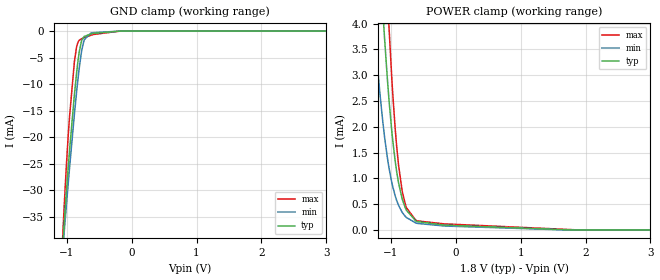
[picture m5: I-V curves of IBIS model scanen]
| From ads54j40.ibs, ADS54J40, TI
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|   scanen Model
[Model]   scanen
Model_type   Input
Vinl = 0.4
Vinh = 1.2
|   typ   min   max
|   (nom PVT)   (fast PVT)   (slow PVT)
|Average
C_comp   1.329e-12   1.282e-12   1.361e-12
| Where nom  PVT is Nominal Process, 1.8V, 25C
|   Fast PVT is Strong Process,  1.9V, -40C
|   Slow PVT is Weak Process,   1.7V, 85C
[Voltage Range]   1.8   1.7   1.9
|Ambient Temperature   25   85   -40
|Junction Temperature
[Temperature Range]   25   85   -40
[Power Clamp Reference]   1.8   1.7   1.9
[GND Clamp Reference]   0   0   0
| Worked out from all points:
|   GND clamp passes 1 mA (typ) near -0.73 V on its own axis
|   POWER clamp passes 1 mA (typ) near -0.90 V on its own axis
[GND Clamp]
|   Voltage   I(typ)   I(min)   I(max)
-1.8V     -253.9mA   -233.1mA   -272.1mA
-1.072V   -42.59mA   -42.97mA   -41.16mA
-1.057V   -39.51mA   -40.55mA   -37.19mA
-1.039V   -35.98mA   -37.69mA   -32.62mA
-958.3mV  -22.65mA   -25.91mA   -16.25mA
-882.3mV  -11.96mA   -15.62mA   -5.724mA
-848.1mV  -7.815mA   -11.39mA   -2.936mA
-806.4mV  -3.809mA   -6.82mA    -1.712mA
-732.2mV  -1.014mA   -1.647mA   -1.25mA
-630.4mV  -542.4uA   -390.4uA   -803.9uA
-180mV    -8.61uA    -7.386uA   -10.29uA
3.6V      0A         0A         0A
[POWER Clamp]
|   Voltage   I(typ)   I(min)   I(max)
-1.8V     24.9mA     16.77mA    34.61mA
-1.251V   7.237mA    3.849mA    11.04mA
-1.173V   5.291mA    2.673mA    8.221mA
-1.101V   3.759mA    1.827mA    5.905mA
-1.028V   2.483mA    1.186mA    3.878mA
-973.8mV  1.747mA    844.2uA    2.657mA
-935.5mV  1.337mA    662.1uA    1.967mA
-884.2mV  918.9uA    479.8uA    1.265mA
-829.1mV  610.6uA    344.9uA    768.4uA
-763.2mV  383.2uA    241.7uA    435.2uA
-618.5mV  177.2uA    136.5uA    190.3uA
3.6V      0A         0A         0A
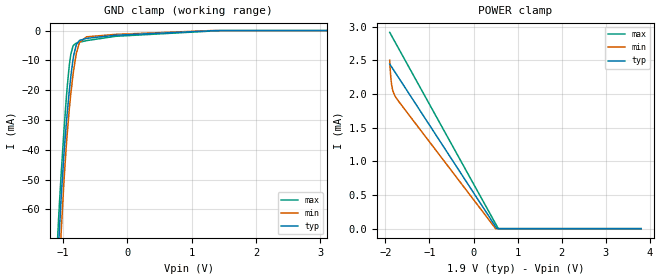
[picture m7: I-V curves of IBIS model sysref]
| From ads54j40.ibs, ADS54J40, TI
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|   sysref Model
[Model]   sysref
Model_type   Input
Vinl = 0.35
Vinh = 1.4
|   typ   min   max
|   (nom PVT)   (fast PVT)   (slow PVT)
|Average
C_comp   3.485e-13   3.130e-13   3.874e-13
| Where nom  PVT is Nominal Process, 1.9V, 25C
|   Fast PVT is Strong Process,  2V, -40C
|   Slow PVT is Weak Process,   1.8V, 85C
[Voltage Range]   1.9   1.8   2
|Ambient Temperature   25   85   -40
|Junction Temperature
[Temperature Range]   25   85   -40
[Power Clamp Reference]   1.9   1.8   2
[GND Clamp Reference]   0   0   0
[GND Clamp]
|   Voltage   I(typ)   I(min)   I(max)
-1.9V     -524.7mA   -521.4mA   -532.5mA
-1.116V   -94mA      -107.5mA   -83.3mA
-1.076V   -74.84mA   -87.97mA   -65.35mA
-1.062V   -68.72mA   -81.5mA    -59.74mA
-1.032V   -56.71mA   -68.36mA   -48.66mA
-953.2mV  -31.81mA   -39.37mA   -23.39mA
-902.8mV  -19.84mA   -26.01mA   -11.37mA
-836mV    -8.345mA   -13.13mA   -4.879mA
-746.7mV  -3.325mA   -4.057mA   -3.909mA
-638.2mV  -2.619mA   -2.093mA   -3.377mA
-190mV    -1.569mA   -1.28mA    -1.928mA
3.8V      0A         0A         0A
[POWER Clamp]
|   Voltage   I(typ)   I(min)   I(max)
-1.9V     2.445mA    2.502mA    2.914mA
-1.89V    2.435mA    2.377mA    2.902mA
-1.879V   2.424mA    2.275mA    2.889mA
-1.866V   2.41mA     2.186mA    2.874mA
-1.848V   2.392mA    2.104mA    2.852mA
-1.812V   2.356mA    2.014mA    2.809mA
-1.752V   2.296mA    1.941mA    2.739mA
499.4mV   31.12uA    1.188uA    73.31uA
530.1mV   249.3nA    0A         36.99uA
560mV     0A         0A         1.625uA
3.8V      0A         0A         0A
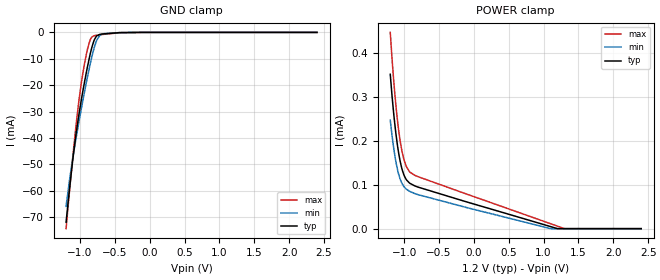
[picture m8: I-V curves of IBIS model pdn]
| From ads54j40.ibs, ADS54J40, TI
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|   pdn Model
[Model]   pdn
Model_type   Input
Vinl = 0.4
Vinh = 1.2
|   typ   min   max
|   (nom PVT)   (fast PVT)   (slow PVT)
|Average
C_comp   1.124e-12   1.105e-12   1.153e-12
| Where nom  PVT is Nominal Process, 1.2V, 25C
|   Fast PVT is Strong Process,  1.3V, -40C
|   Slow PVT is Weak Process,   1.1V, 85C
[Voltage Range]   1.2   1.1   1.3
|Ambient Temperature   25   85   -40
|Junction Temperature
[Temperature Range]   25   85   -40
[Power Clamp Reference]   1.2   1.1   1.3
[GND Clamp Reference]   0   0   0
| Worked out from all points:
|   GND clamp passes 1 mA (typ) near -0.74 V on its own axis
[GND Clamp]
|   Voltage   I(typ)   I(min)   I(max)
-1.2V     -71.86mA   -65.9mA    -74.32mA
-1.092V   -45.65mA   -45.67mA   -44.08mA
-1.021V   -32.04mA   -34.72mA   -27.03mA
-984.4mV  -26.05mA   -29.37mA   -19.75mA
-934.8mV  -18.7mA    -22.44mA   -11.76mA
-893.2mV  -13.04mA   -16.9mA    -6.38mA
-858.1mV  -8.699mA   -12.5mA    -3.111mA
-824.3mV  -5.13mA    -8.61mA    -1.618mA
-758mV    -1.281mA   -2.843mA   -1.058mA
-716mV    -758.6uA   -1.133mA   -914.2uA
-657.7mV  -545.5uA   -474.8uA   -726.7uA
2.4V      0A         0A         0A
[POWER Clamp]
|   Voltage   I(typ)   I(min)   I(max)
-1.2V     350.9uA    246.6uA    446.3uA
-1.173V   298.6uA    209.2uA    382.6uA
-1.127V   227.3uA    159.6uA    294.2uA
-1.093V   185.8uA    132.4uA    241.4uA
-1.066V   159.5uA    116.4uA    207.6uA
-1.03V    134.6uA    102.4uA    174.5uA
-998.5mV  120.2uA    94.69uA    154.4uA
-963.6mV  110.2uA    89.16uA    139.5uA
-916.6mV  102.9uA    84.43uA    128.3uA
1.099V    4.727uA    39.38nA    11.28uA
1.3V      0A         0A         0A
2.4V      0A         0A         0A
